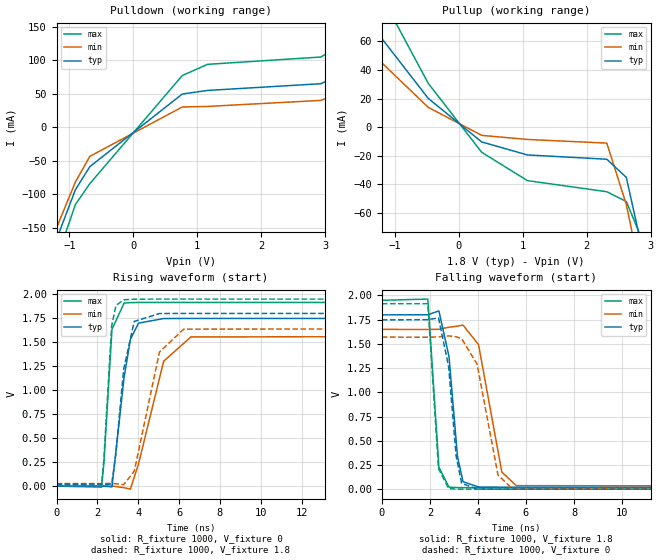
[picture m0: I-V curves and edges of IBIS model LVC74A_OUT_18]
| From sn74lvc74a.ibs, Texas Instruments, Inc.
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[Model]   LVC74A_OUT_18
Model_type  Output
Vref =   0
Rref =   1000
Cref =   30p
Vmeas =   0.9
| variable   typ   min   max
C_comp   8.86pF   7.08pF   12.02pF
| C_pullup   8.02pF   7.08pF   9.01pF
| C_pulldown   9.69pF   7.63pF   12.02pF
[Temperature Range]   40   100   -40
| Ambient temperature   25   85   -40
[Voltage range]   1.8   1.65   1.95
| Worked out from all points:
|   slope of the pulldown table from 0 to 0.27 V, typ, clamps not added: 12.3 ohm
|   slope of the pullup table from 0 to 0.27 V, typ, clamps not added: 33.2 ohm
|   rising waveform, R_fixture 1000, V_fixture 0: 20-80 % time 535ps typ, 1.06ns min, 306ps max; typ from 0 V to 1.75 V
|   falling waveform, R_fixture 1000, V_fixture 1.8: 20-80 % time 368ps typ, 651ps min, 232ps max; typ from 1.8 V to 0.02 V
|   rising waveform, R_fixture 1000, V_fixture 1.8: 20-80 % time 505ps typ, 927ps min, 298ps max; typ from 0.02 V to 1.8 V
|   falling waveform, R_fixture 1000, V_fixture 0: 20-80 % time 364ps typ, 674ps min, 231ps max; typ from 1.75 V to 0 V
[Pulldown]
| LVC74A_OUT_18
|   Voltage   I(typ)   I(min)   I(max)
-5.5V     -1.298A    -1.208A    -1.448A
-1.32V    -200.1mA   -179.9mA   -235.1mA
-1.145V   -153.7mA   -137.6mA   -182.3mA
-905mV    -93.43mA   -81.99mA   -115.5mA
-680mV    -58.99mA   -43.64mA   -84.42mA
765mV     49.45mA    30.13mA    77.07mA
1.16V     54.81mA    30.94mA    93.81mA
2.93V     64.86mA    39.93mA    104.7mA
4.255V    122.1mA    85.83mA    180.6mA
5.24V     183.3mA    134.8mA    264.4mA
6.12V     245.4mA    185mA      348.9mA
11V       661.1mA    525.4mA    909.8mA
[Pullup]
| LVC74A_OUT_18
|   Voltage   I(typ)   I(min)   I(max)
-5.5V     381.6mA    297.7mA    537.1mA
-2.87V    173.6mA    131.2mA    249.2mA
-2.26V    129.7mA    96.79mA    187.7mA
-1.565V   83.03mA    60.67mA    121.7mA
-475mV    20.12mA    13.83mA    30.66mA
360mV     -10.35mA   -5.755mA   -17.57mA
1.075V    -19.45mA   -8.616mA   -37.44mA
2.315V    -22.46mA   -11.17mA   -45.19mA
2.62V     -35.13mA   -54.12mA   -52.05mA
2.94V     -99.84mA   -123mA     -86.61mA
3.11V     -140mA     -161.7mA   -128.1mA
11V       -2.215A    -2.111A    -2.415A
[Ramp]
| LVC74A_OUT_18
| variable   typ   min   max
dV/dt_r   1.07/5.45E-10   0.96/1.08E-09   1.16/3.16E-10
dV/dt_f   1.09/3.81E-10   1.01/6.79E-10   1.18/2.45E-10
R_load = 1000
[Rising Waveform]
| LVC74A_OUT_18
R_fixture =   1000
C_fixture =   0
L_fixture =   0
V_fixture =   0
V_fixture_min = 0
V_fixture_max = 0
|   Time   V(typ)   V(min)   V(max)
0s        445.9pV    2.368nV    1.849nV
2.205ns   570.9uV    274.1uV    -11.32mV
2.315ns   -1.278mV   366.5uV    227.4mV
2.715ns   -8.374mV   843.1uV    1.635V
3.31ns    1.138V     -16.97mV   1.908V
3.615ns   1.528V     -32.32mV   1.913V
4.015ns   1.699V     231mV      1.915V
5.245ns   1.747V     1.302V     1.915V
6.58ns    1.748V     1.555V     1.915V
50ns      1.748V     1.57V      1.915V
[Falling Waveform]
| LVC74A_OUT_18
R_fixture =   1000
C_fixture =   0
L_fixture =   0
V_fixture =   1.8
V_fixture_min = 1.65
V_fixture_max = 1.95
|   Time   V(typ)   V(min)   V(max)
0s        1.8V       1.65V      1.95V
1.915ns   1.801V     1.649V     1.963V
2.375ns   1.841V     1.651V     228.7mV
2.795ns   1.371V     1.672V     20.88mV
3.15ns    336.4mV    1.684V     16.28mV
3.38ns    76.56mV    1.694V     15.64mV
4.025ns   22.62mV    1.493V     15.31mV
4.995ns   20.39mV    177.3mV    15.28mV
5.595ns   20.31mV    36.32mV    15.28mV
50ns      20.29mV    26.1mV     15.28mV
[Rising Waveform]
| LVC74A_OUT_18
R_fixture =   1000
C_fixture =   0
L_fixture =   0
V_fixture =   1.8
V_fixture_min = 1.65
V_fixture_max = 1.95
|   Time   V(typ)   V(min)   V(max)
0s        20.29mV    26.1mV     15.28mV
2.205ns   20.7mV     26.33mV    10.22mV
2.315ns   18.88mV    26.38mV    270.4mV
2.7ns     19.91mV    26.59mV    1.671V
2.91ns    341.9mV    24.56mV    1.883V
3.285ns   1.217V     14.05mV    1.942V
3.805ns   1.717V     154mV      1.949V
5.04ns    1.799V     1.398V     1.95V
6.225ns   1.8V       1.636V     1.95V
50ns      1.8V       1.65V      1.95V
[Falling Waveform]
| LVC74A_OUT_18
R_fixture =   1000
C_fixture =   0
L_fixture =   0
V_fixture =   0
V_fixture_min = 0
V_fixture_max = 0
|   Time   V(typ)   V(min)   V(max)
0s        1.748V     1.57V      1.915V
1.915ns   1.75V      1.569V     1.915V
2.36ns    1.769V     1.572V     211.8mV
2.78ns    1.266V     1.583V     5.533mV
3.095ns   338.4mV    1.573V     1.124mV
3.32ns    60.09mV    1.555V     418.1uV
3.965ns   2.086mV    1.291V     30.44uV
4.835ns   109.9uV    146.6mV    1.276uV
5.41ns    18.46uV    8.617mV    403.5nV
50ns      -6.066nV   -4.873nV   1.388nV
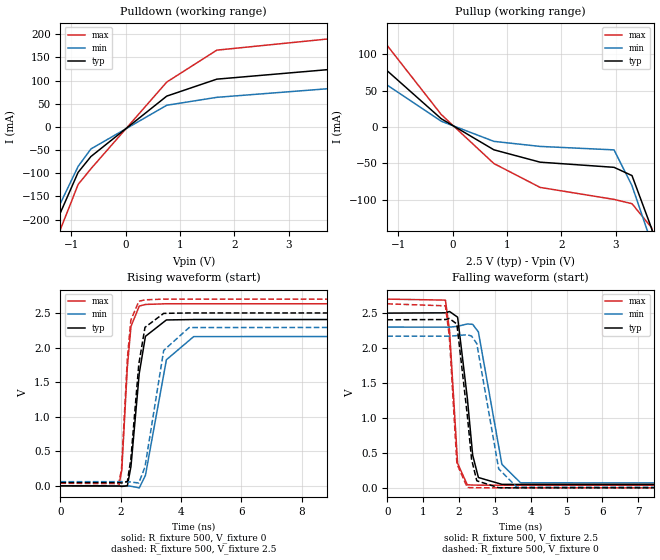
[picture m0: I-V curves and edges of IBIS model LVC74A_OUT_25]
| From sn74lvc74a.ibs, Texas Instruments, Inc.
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[Model]   LVC74A_OUT_25
Model_type  Output
Vref =   0
Rref =   500
Cref =   30p
Vmeas =   1.25
| variable   typ   min   max
C_comp   8.33pF   6.85pF   10.56pF
| C_pullup   7.86pF   6.85pF   9.15pF
| C_pulldown   8.80pF   7.49pF   10.56pF
[Temperature Range]   40   100   -40
| Ambient temperature   25   85   -40
[Voltage range]   2.5   2.3   2.7
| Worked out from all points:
|   slope of the pulldown table from 0 to 0.375 V, typ, clamps not added: 10.5 ohm
|   slope of the pullup table from 0 to 0.375 V, typ, clamps not added: 21.5 ohm
|   rising waveform, R_fixture 500, V_fixture 0: 20-80 % time 319ps typ, 515ps min, 212ps max; typ from 0 V to 2.4 V
|   falling waveform, R_fixture 500, V_fixture 2.5: 20-80 % time 260ps typ, 391ps min, 171ps max; typ from 2.5 V to 0.048 V
|   rising waveform, R_fixture 500, V_fixture 2.5: 20-80 % time 303ps typ, 467ps min, 205ps max; typ from 0.048 V to 2.5 V
|   falling waveform, R_fixture 500, V_fixture 0: 20-80 % time 252ps typ, 380ps min, 169ps max; typ from 2.4 V to 0 V
[Pulldown]
| LVC74A_OUT_25
|   Voltage   I(typ)   I(min)   I(max)
-5.5V     -1.338A    -1.236A    -1.508A
-1.685V   -319.5mA   -287.3mA   -374mA
-1.315V   -215.7mA   -192.9mA   -255.3mA
-875mV    -98.06mA   -85.22mA   -124.2mA
-640mV    -63.9mA    -47.53mA   -90.34mA
755mV     66.51mA    46.78mA    96.81mA
1.675V    103.1mA    63.86mA    165.7mA
3.95V     126mA      84.59mA    192.6mA
4.625V    156.6mA    109.5mA    232.2mA
5.715V    221.9mA    162.2mA    320.7mA
6.97V     311.4mA    234.9mA    442.1mA
11V       655.1mA    516.7mA    904.6mA
[Pullup]
| LVC74A_OUT_25
|   Voltage   I(typ)   I(min)   I(max)
-5.5V     421.5mA    330.4mA    591.7mA
-2.935V   206.4mA    158mA      294.1mA
-2.225V   150.8mA    114.2mA    216.3mA
-1.56V    101.1mA    75.48mA    146.3mA
-210mV    11.37mA    7.924mA    17.21mA
760mV     -31.49mA   -19.87mA   -50.4mA
1.61V     -48.51mA   -26.83mA   -83.25mA
2.97V     -55.62mA   -31.6mA    -99.77mA
3.3V      -66.98mA   -80.89mA   -105.7mA
3.655V    -138.6mA   -158.9mA   -138.2mA
3.755V    -162.5mA   -181.9mA   -161.6mA
11V       -2.086A    -1.98A     -2.296A
[Ramp]
| LVC74A_OUT_25
| variable   typ   min   max
dV/dt_r   1.45/3.31E-10   1.32/5.22E-10   1.59/2.15E-10
dV/dt_f   1.50/2.75E-10   1.37/4.08E-10   1.61/1.84E-10
R_load = 500
[Rising Waveform]
| LVC74A_OUT_25
R_fixture =   500
C_fixture =   0
L_fixture =   0
V_fixture =   0
V_fixture_min = 0
V_fixture_max = 0
|   Time   V(typ)   V(min)   V(max)
0s        529.4pV    2.141nV    1.838nV
1.935ns   -1.589mV   551.5uV    -5.024mV
2.035ns   -8.956mV   675.2uV    227.9mV
2.22ns    505.5uV    -636.7uV   1.72V
2.34ns    281.3mV    -5.925mV   2.305V
2.615ns   1.628V     -29.11mV   2.6V
2.82ns    2.162V     151.5mV    2.623V
3.515ns   2.399V     1.823V     2.633V
4.42ns    2.405V     2.158V     2.633V
50ns      2.405V     2.17V      2.633V
[Falling Waveform]
| LVC74A_OUT_25
R_fixture =   500
C_fixture =   0
L_fixture =   0
V_fixture =   2.5
V_fixture_min = 2.3
V_fixture_max = 2.7
|   Time   V(typ)   V(min)   V(max)
0s        2.5V       2.3V       2.7V
1.62ns    2.504V     2.299V     2.686V
1.735ns   2.523V     2.299V     2.251V
1.96ns    2.442V     2.311V     351.1mV
2.23ns    1.29V      2.345V     43.68mV
2.38ns    469.1mV    2.339V     40.36mV
2.54ns    147.9mV    2.231V     39.3mV
3.195ns   50.28mV    336.1mV    37.19mV
3.715ns   48.59mV    72.11mV    37.07mV
50ns      48.34mV    60.19mV    37.06mV
[Rising Waveform]
| LVC74A_OUT_25
R_fixture =   500
C_fixture =   0
L_fixture =   0
V_fixture =   2.5
V_fixture_min = 2.3
V_fixture_max = 2.7
|   Time   V(typ)   V(min)   V(max)
0s        48.34mV    60.19mV    37.06mV
1.93ns    46.91mV    60.58mV    31.68mV
2.025ns   41.09mV    60.61mV    231.5mV
2.22ns    62.11mV    59.2mV     1.841V
2.335ns   382.7mV    54.73mV    2.394V
2.6ns     1.761V     41.24mV    2.669V
2.805ns   2.292V     273.7mV    2.69V
3.425ns   2.494V     1.958V     2.7V
4.27ns    2.5V       2.289V     2.7V
50ns      2.5V       2.3V       2.7V
[Falling Waveform]
| LVC74A_OUT_25
R_fixture =   500
C_fixture =   0
L_fixture =   0
V_fixture =   0
V_fixture_min = 0
V_fixture_max = 0
|   Time   V(typ)   V(min)   V(max)
0s        2.405V     2.17V      2.633V
1.62ns    2.408V     2.17V      2.604V
1.73ns    2.423V     2.17V      2.165V
1.94ns    2.344V     2.178V     345.3mV
2.23ns    1.042V     2.191V     5.189mV
2.35ns    407mV      2.171V     3.174mV
2.495ns   100.9mV    2.063V     2.307mV
3.105ns   2.161mV    273.1mV    183.6uV
3.61ns    284.1uV    9.965mV    24.56uV
50ns      -394.6pV   -13.97nV   -374.2pV
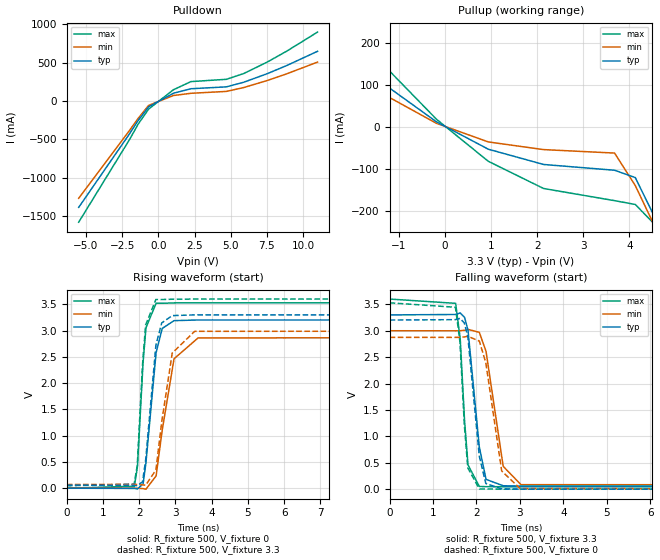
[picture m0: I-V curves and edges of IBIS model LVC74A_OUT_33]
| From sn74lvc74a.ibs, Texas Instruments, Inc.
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[Model]   LVC74A_OUT_33
Model_type  Output
Vref =   0
Rref =   500
Cref =   50p
Vmeas =   1.5
| variable   typ   min   max
C_comp   7.96pF   6.65pF   9.72pF
| C_pullup   7.68pF   6.65pF   9.20pF
| C_pulldown   8.23pF   7.19pF   9.72pF
[Temperature Range]   40   100   -40
| Ambient temperature   25   85   -40
[Voltage range]   3.3   3   3.6
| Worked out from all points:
|   slope of the pulldown table from 0 to 0.495 V, typ, clamps not added: 9.41 ohm
|   slope of the pullup table from 0 to 0.495 V, typ, clamps not added: 16.3 ohm
|   rising waveform, R_fixture 500, V_fixture 0: 20-80 % time 255ps typ, 354ps min, 173ps max; typ from 0 V to 3.2 V
|   falling waveform, R_fixture 500, V_fixture 3.3: 20-80 % time 211ps typ, 291ps min, 148ps max; typ from 3.3 V to 0.058 V
|   rising waveform, R_fixture 500, V_fixture 3.3: 20-80 % time 247ps typ, 332ps min, 169ps max; typ from 0.058 V to 3.3 V
|   falling waveform, R_fixture 500, V_fixture 0: 20-80 % time 207ps typ, 284ps min, 148ps max; typ from 3.2 V to 0 V
[Pulldown]
| LVC74A_OUT_33
|   Voltage   I(typ)   I(min)   I(max)
-5.5V     -1.385A    -1.267A    -1.579A
-1.995V   -428.1mA   -383.5mA   -502.6mA
-1.74V    -353.8mA   -316.2mA   -417.2mA
-1.385V   -250.1mA   -222.4mA   -297.7mA
-670mV    -73.89mA   -55.82mA   -104mA
1.045V    102.7mA    73.28mA    148.3mA
2.255V    161.4mA    102mA      254.8mA
4.7V      185.9mA    126.5mA    284mA
5.89V     245.5mA    176.5mA    358.7mA
7.535V    358.5mA    269.1mA    510.1mA
8.86V     463.2mA    355.2mA    650.5mA
11V       649.7mA    508.9mA    900.2mA
[Pullup]
| LVC74A_OUT_33
|   Voltage   I(typ)   I(min)   I(max)
-5.5V     463.1mA    362.9mA    650.9mA
-3.92V    320.8mA    248.7mA    453.7mA
-3.005V   240.5mA    184.9mA    342mA
-2.18V    170.1mA    129.4mA    243.4mA
-185mV    12.69mA    9.087mA    18.89mA
940mV     -52.46mA   -35.16mA   -81.24mA
2.14V     -88.79mA   -53.41mA   -145.9mA
3.68V     -102.5mA   -61.66mA   -174.8mA
4.13V     -120mA     -139mA     -183.9mA
4.63V     -231.8mA   -254.2mA   -240.2mA
4.755V    -263.1mA   -284.1mA   -272.9mA
11V       -1.946A    -1.847A    -2.161A
[Ramp]
| LVC74A_OUT_33
| variable   typ   min   max
dV/dt_r   1.94/2.64E-10   1.74/3.62E-10   2.13/1.87E-10
dV/dt_f   1.97/2.21E-10   1.79/3.04E-10   2.14/1.49E-10
R_load = 500
[Rising Waveform]
| LVC74A_OUT_33
R_fixture =   500
C_fixture =   0
L_fixture =   0
V_fixture =   0
V_fixture_min = 0
V_fixture_max = 0
|   Time   V(typ)   V(min)   V(max)
0s        634.9pV    2.111nV    1.921nV
1.865ns   -4.51mV    801.8uV    37.01mV
1.95ns    -14.32mV   244.3uV    407.2mV
2.105ns   77.99mV    -8.486mV   2.387V
2.185ns   483.9mV    -18.78mV   3.053V
2.465ns   2.581V     233.2mV    3.52V
2.635ns   3.041V     1.11V      3.52V
2.96ns    3.189V     2.463V     3.527V
3.625ns   3.202V     2.861V     3.529V
50ns      3.203V     2.875V     3.529V
[Falling Waveform]
| LVC74A_OUT_33
R_fixture =   500
C_fixture =   0
L_fixture =   0
V_fixture =   3.3
V_fixture_min = 3
V_fixture_max = 3.6
|   Time   V(typ)   V(min)   V(max)
0s        3.3V       3V         3.6V
1.52ns    3.308V     2.999V     3.519V
1.625ns   3.337V     3.001V     2.849V
1.725ns   3.255V     3.009V     1.298V
1.805ns   3.008V     3.026V     459.3mV
2.065ns   798.5mV    2.97V      51.29mV
2.22ns    185.4mV    2.609V     47.23mV
2.615ns   64.55mV    431.6mV    45.82mV
3.025ns   59.01mV    85.05mV    45.23mV
50ns      57.93mV    70.6mV     45.09mV
[Rising Waveform]
| LVC74A_OUT_33
R_fixture =   500
C_fixture =   0
L_fixture =   0
V_fixture =   3.3
V_fixture_min = 3
V_fixture_max = 3.6
|   Time   V(typ)   V(min)   V(max)
0s        57.93mV    70.6mV     45.09mV
1.86ns    54.01mV    71.23mV    78.88mV
1.945ns   45.7mV     70.75mV    430.1mV
2.09ns    122.2mV    63.72mV    2.348V
2.175ns   523.9mV    55.1mV     3.106V
2.46ns    2.723V     345.9mV    3.592V
2.62ns    3.146V     1.263V     3.591V
2.91ns    3.285V     2.572V     3.597V
3.53ns    3.299V     2.986V     3.6V
50ns      3.3V       3V         3.6V
[Falling Waveform]
| LVC74A_OUT_33
R_fixture =   500
C_fixture =   0
L_fixture =   0
V_fixture =   0
V_fixture_min = 0
V_fixture_max = 0
|   Time   V(typ)   V(min)   V(max)
0s        3.203V     2.875V     3.529V
1.515ns   3.21V      2.874V     3.445V
1.62ns    3.234V     2.876V     2.779V
1.72ns    3.148V     2.883V     1.219V
1.8ns     2.889V     2.895V     403mV
2.065ns   621.2mV    2.805V     5.593mV
2.215ns   107mV      2.394V     2.443mV
2.58ns    5.99mV     345mV      793uV
3.005ns   1.04mV     10.95mV    145.8uV
50ns      -30.48pV   5.531nV    1.973nV
